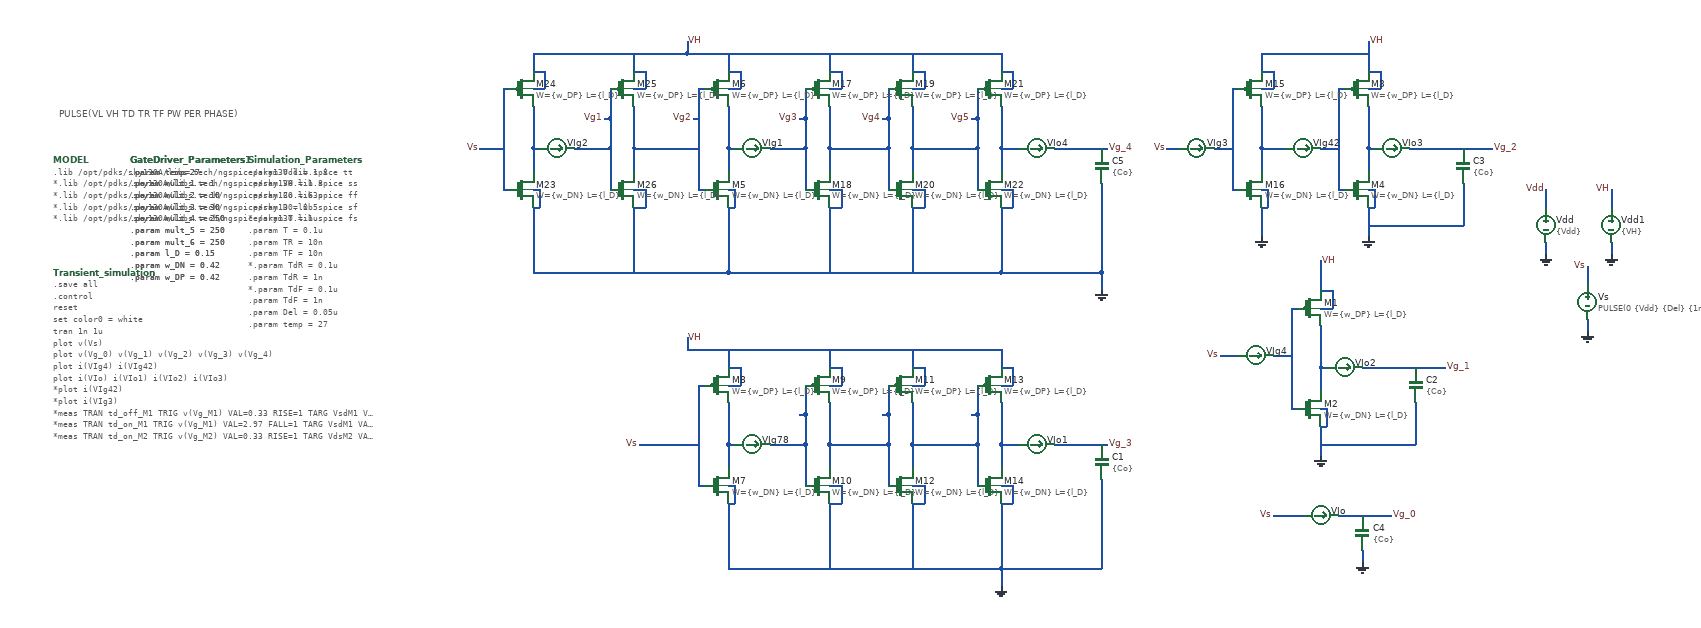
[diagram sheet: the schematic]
v {xschem version=3.4.5 file_version=1.2
}
G {}
K {}
V {}
S {}
E {}
T {PULSE(VL VH TD TR TF PW PER PHASE) 
} -1560 -1540 0 0 0.4 0.4 {}
N 950 -1400 950 -1370 {
lab=Vdd}
N 950 -1310 950 -1290 {
lab=GND}
N 1020 -1270 1020 -1240 {
lab=Vs}
N 1020 -1180 1020 -1160 {
lab=GND}
N 1060 -1400 1060 -1370 {
lab=VH}
N 1060 -1310 1060 -1290 {
lab=GND}
N 570 -1100 570 -1060 {
lab=#net1}
N 570 -1170 570 -1100 {
lab=#net1}
N 570 -1030 580 -1030 {
lab=GND}
N 580 -1030 580 -1000 {
lab=GND}
N 570 -1000 580 -1000 {
lab=GND}
N 570 -1200 590 -1200 {
lab=VH}
N 590 -1230 590 -1200 {
lab=VH}
N 570 -1230 590 -1230 {
lab=VH}
N 570 -1100 580 -1100 {
lab=#net1}
N 520 -1200 520 -1030 {
lab=#net2}
N 520 -1030 530 -1030 {
lab=#net2}
N 570 -1000 570 -950 {
lab=GND}
N 570 -1280 570 -1230 {
lab=VH}
N 640 -1100 730 -1100 {
lab=Vg_1}
N 570 -970 730 -970 {
lab=GND}
N 730 -1040 730 -970 {
lab=GND}
N 490 -1120 520 -1120 {
lab=#net2}
N 730 -1100 780 -1100 {
lab=Vg_1}
N 400 -1120 430 -1120 {
lab=Vs}
N 650 -1470 650 -1430 {
lab=#net3}
N 650 -1540 650 -1470 {
lab=#net3}
N 650 -1400 660 -1400 {
lab=GND}
N 660 -1400 660 -1370 {
lab=GND}
N 650 -1370 660 -1370 {
lab=GND}
N 650 -1570 670 -1570 {
lab=VH}
N 670 -1600 670 -1570 {
lab=VH}
N 650 -1600 670 -1600 {
lab=VH}
N 650 -1470 660 -1470 {
lab=#net3}
N 600 -1570 610 -1570 {
lab=#net4}
N 600 -1570 600 -1400 {
lab=#net4}
N 600 -1400 610 -1400 {
lab=#net4}
N 650 -1370 650 -1320 {
lab=GND}
N 650 -1650 650 -1600 {
lab=VH}
N 720 -1470 810 -1470 {
lab=Vg_2}
N 650 -1340 810 -1340 {
lab=GND}
N 810 -1410 810 -1340 {
lab=GND}
N 570 -1470 600 -1470 {
lab=#net4}
N 810 -1470 860 -1470 {
lab=Vg_2}
N 480 -1470 510 -1470 {
lab=#net5}
N 470 -1470 470 -1430 {
lab=#net5}
N 470 -1540 470 -1470 {
lab=#net5}
N 470 -1400 480 -1400 {
lab=GND}
N 480 -1400 480 -1370 {
lab=GND}
N 470 -1370 480 -1370 {
lab=GND}
N 470 -1570 490 -1570 {
lab=VH}
N 490 -1600 490 -1570 {
lab=VH}
N 470 -1600 490 -1600 {
lab=VH}
N 470 -1470 480 -1470 {
lab=#net5}
N 420 -1570 430 -1570 {
lab=#net6}
N 420 -1570 420 -1400 {
lab=#net6}
N 420 -1400 430 -1400 {
lab=#net6}
N 470 -1370 470 -1320 {
lab=GND}
N 390 -1470 420 -1470 {
lab=#net6}
N 470 -1610 470 -1600 {
lab=VH}
N 470 -1630 650 -1630 {
lab=VH}
N 310 -1470 330 -1470 {
lab=Vs}
N 470 -1630 470 -1610 {
lab=VH}
N 600 -850 640 -850 {
lab=Vg_0}
N 490 -850 540 -850 {
lab=Vs}
N 640 -790 640 -770 {
lab=GND}
N 640 -850 690 -850 {
lab=Vg_0}
N 120 -970 170 -970 {
lab=Vg_3}
N -500 -1150 -500 -1130 {
lab=VH}
N 170 -970 200 -970 {
lab=Vg_3}
N 200 -970 210 -970 {
lab=Vg_3}
N 50 -970 60 -970 {
lab=#net7}
N -430 -970 -430 -930 {
lab=#net8}
N -140 -760 30 -760 {
lab=GND}
N -310 -760 -140 -760 {
lab=GND}
N -550 -970 -480 -970 {
lab=Vs}
N -300 -970 -300 -900 {
lab=#net9}
N -430 -1040 -430 -970 {
lab=#net8}
N -300 -1020 -300 -970 {
lab=#net9}
N -260 -970 -260 -930 {
lab=#net10}
N -140 -1130 30 -1130 {
lab=VH}
N -310 -1130 -140 -1130 {
lab=VH}
N -500 -1130 -310 -1130 {
lab=VH}
N -580 -970 -550 -970 {
lab=Vs}
N 30 -760 30 -730 {
lab=GND}
N -260 -970 -220 -970 {
lab=#net10}
N -260 -1040 -260 -970 {
lab=#net10}
N -430 -900 -420 -900 {
lab=GND}
N -420 -900 -420 -870 {
lab=GND}
N -430 -870 -420 -870 {
lab=GND}
N -260 -900 -240 -900 {
lab=GND}
N -240 -900 -240 -870 {
lab=GND}
N -260 -870 -240 -870 {
lab=GND}
N -430 -1070 -410 -1070 {
lab=VH}
N -410 -1100 -410 -1070 {
lab=VH}
N -430 -1100 -410 -1100 {
lab=VH}
N -260 -1070 -240 -1070 {
lab=VH}
N -240 -1100 -240 -1070 {
lab=VH}
N -260 -1100 -240 -1100 {
lab=VH}
N -360 -970 -300 -970 {
lab=#net9}
N -430 -970 -420 -970 {
lab=#net8}
N -310 -1020 -300 -1020 {
lab=#net9}
N -300 -1070 -300 -1020 {
lab=#net9}
N -480 -1070 -470 -1070 {
lab=Vs}
N -480 -1070 -480 -900 {
lab=Vs}
N -480 -900 -470 -900 {
lab=Vs}
N -430 -870 -430 -760 {
lab=GND}
N -430 -760 -300 -760 {
lab=GND}
N -430 -1130 -430 -1100 {
lab=VH}
N -260 -1130 -260 -1100 {
lab=VH}
N -260 -870 -260 -760 {
lab=GND}
N -160 -970 -160 -900 {
lab=#net10}
N -160 -1020 -160 -970 {
lab=#net10}
N -120 -970 -120 -930 {
lab=#net11}
N -120 -970 -80 -970 {
lab=#net11}
N -120 -1040 -120 -970 {
lab=#net11}
N -120 -900 -100 -900 {
lab=GND}
N -100 -900 -100 -870 {
lab=GND}
N -120 -870 -100 -870 {
lab=GND}
N -120 -1070 -100 -1070 {
lab=VH}
N -100 -1100 -100 -1070 {
lab=VH}
N -120 -1100 -100 -1100 {
lab=VH}
N -220 -970 -160 -970 {
lab=#net10}
N -170 -1020 -160 -1020 {
lab=#net10}
N -160 -1070 -160 -1020 {
lab=#net10}
N -120 -1130 -120 -1100 {
lab=VH}
N -120 -870 -120 -760 {
lab=GND}
N -10 -970 -10 -900 {
lab=#net11}
N -10 -1020 -10 -970 {
lab=#net11}
N 30 -970 30 -930 {
lab=#net7}
N 30 -1040 30 -970 {
lab=#net7}
N 30 -900 50 -900 {
lab=GND}
N 50 -900 50 -870 {
lab=GND}
N 30 -870 50 -870 {
lab=GND}
N 30 -1070 50 -1070 {
lab=VH}
N 50 -1100 50 -1070 {
lab=VH}
N 30 -1100 50 -1100 {
lab=VH}
N -70 -970 -10 -970 {
lab=#net11}
N -20 -1020 -10 -1020 {
lab=#net11}
N -10 -1070 -10 -1020 {
lab=#net11}
N 30 -1130 30 -1100 {
lab=VH}
N 30 -870 30 -760 {
lab=GND}
N -80 -970 -60 -970 {
lab=#net11}
N 30 -970 60 -970 {
lab=#net7}
N 200 -910 200 -760 {
lab=GND}
N 30 -760 200 -760 {
lab=GND}
N 520 -1200 530 -1200 {
lab=#net2}
N 120 -1470 170 -1470 {
lab=Vg_4}
N -500 -1650 -500 -1630 {
lab=VH}
N 170 -1470 200 -1470 {
lab=Vg_4}
N 200 -1470 210 -1470 {
lab=Vg_4}
N 50 -1470 60 -1470 {
lab=#net12}
N -430 -1470 -430 -1430 {
lab=#net13}
N -140 -1260 30 -1260 {
lab=GND}
N -310 -1260 -140 -1260 {
lab=GND}
N -550 -1470 -480 -1470 {
lab=Vg2}
N -300 -1470 -300 -1400 {
lab=Vg3}
N -430 -1540 -430 -1470 {
lab=#net13}
N -300 -1520 -300 -1470 {
lab=Vg3}
N -260 -1470 -260 -1430 {
lab=Vg4}
N -140 -1630 30 -1630 {
lab=VH}
N -310 -1630 -140 -1630 {
lab=VH}
N -500 -1630 -310 -1630 {
lab=VH}
N 200 -1260 200 -1230 {
lab=GND}
N -260 -1470 -220 -1470 {
lab=Vg4}
N -260 -1540 -260 -1470 {
lab=Vg4}
N -430 -1400 -420 -1400 {
lab=GND}
N -420 -1400 -420 -1370 {
lab=GND}
N -430 -1370 -420 -1370 {
lab=GND}
N -260 -1400 -240 -1400 {
lab=GND}
N -240 -1400 -240 -1370 {
lab=GND}
N -260 -1370 -240 -1370 {
lab=GND}
N -430 -1570 -410 -1570 {
lab=VH}
N -410 -1600 -410 -1570 {
lab=VH}
N -430 -1600 -410 -1600 {
lab=VH}
N -260 -1570 -240 -1570 {
lab=VH}
N -240 -1600 -240 -1570 {
lab=VH}
N -260 -1600 -240 -1600 {
lab=VH}
N -360 -1470 -300 -1470 {
lab=Vg3}
N -430 -1470 -420 -1470 {
lab=#net13}
N -310 -1520 -300 -1520 {
lab=Vg3}
N -300 -1570 -300 -1520 {
lab=Vg3}
N -480 -1570 -470 -1570 {
lab=Vg2}
N -480 -1570 -480 -1400 {
lab=Vg2}
N -480 -1400 -470 -1400 {
lab=Vg2}
N -430 -1370 -430 -1260 {
lab=GND}
N -430 -1260 -300 -1260 {
lab=GND}
N -430 -1630 -430 -1600 {
lab=VH}
N -260 -1630 -260 -1600 {
lab=VH}
N -260 -1370 -260 -1260 {
lab=GND}
N -160 -1470 -160 -1400 {
lab=Vg4}
N -160 -1520 -160 -1470 {
lab=Vg4}
N -120 -1470 -120 -1430 {
lab=Vg5}
N -120 -1470 -80 -1470 {
lab=Vg5}
N -120 -1540 -120 -1470 {
lab=Vg5}
N -120 -1400 -100 -1400 {
lab=GND}
N -100 -1400 -100 -1370 {
lab=GND}
N -120 -1370 -100 -1370 {
lab=GND}
N -120 -1570 -100 -1570 {
lab=VH}
N -100 -1600 -100 -1570 {
lab=VH}
N -120 -1600 -100 -1600 {
lab=VH}
N -220 -1470 -160 -1470 {
lab=Vg4}
N -170 -1520 -160 -1520 {
lab=Vg4}
N -160 -1570 -160 -1520 {
lab=Vg4}
N -120 -1630 -120 -1600 {
lab=VH}
N -120 -1370 -120 -1260 {
lab=GND}
N -10 -1470 -10 -1400 {
lab=Vg5}
N -10 -1520 -10 -1470 {
lab=Vg5}
N 30 -1470 30 -1430 {
lab=#net12}
N 30 -1540 30 -1470 {
lab=#net12}
N 30 -1400 50 -1400 {
lab=GND}
N 50 -1400 50 -1370 {
lab=GND}
N 30 -1370 50 -1370 {
lab=GND}
N 30 -1570 50 -1570 {
lab=VH}
N 50 -1600 50 -1570 {
lab=VH}
N 30 -1600 50 -1600 {
lab=VH}
N -70 -1470 -10 -1470 {
lab=Vg5}
N -20 -1520 -10 -1520 {
lab=Vg5}
N -10 -1570 -10 -1520 {
lab=Vg5}
N 30 -1630 30 -1600 {
lab=VH}
N 30 -1370 30 -1260 {
lab=GND}
N -80 -1470 -60 -1470 {
lab=Vg5}
N 30 -1470 60 -1470 {
lab=#net12}
N 200 -1410 200 -1260 {
lab=GND}
N 30 -1260 200 -1260 {
lab=GND}
N -760 -1470 -760 -1430 {
lab=#net14}
N -630 -1470 -630 -1400 {
lab=Vg1}
N -760 -1540 -760 -1470 {
lab=#net14}
N -630 -1520 -630 -1470 {
lab=Vg1}
N -590 -1470 -590 -1430 {
lab=Vg2}
N -590 -1470 -550 -1470 {
lab=Vg2}
N -590 -1540 -590 -1470 {
lab=Vg2}
N -760 -1400 -750 -1400 {
lab=GND}
N -750 -1400 -750 -1370 {
lab=GND}
N -760 -1370 -750 -1370 {
lab=GND}
N -590 -1400 -570 -1400 {
lab=GND}
N -570 -1400 -570 -1370 {
lab=GND}
N -590 -1370 -570 -1370 {
lab=GND}
N -760 -1570 -740 -1570 {
lab=VH}
N -740 -1600 -740 -1570 {
lab=VH}
N -760 -1600 -740 -1600 {
lab=VH}
N -590 -1570 -570 -1570 {
lab=VH}
N -570 -1600 -570 -1570 {
lab=VH}
N -590 -1600 -570 -1600 {
lab=VH}
N -690 -1470 -630 -1470 {
lab=Vg1}
N -760 -1470 -750 -1470 {
lab=#net14}
N -640 -1520 -630 -1520 {
lab=Vg1}
N -630 -1570 -630 -1520 {
lab=Vg1}
N -810 -1570 -800 -1570 {
lab=Vs}
N -810 -1570 -810 -1400 {
lab=Vs}
N -810 -1400 -800 -1400 {
lab=Vs}
N -760 -1260 -430 -1260 {
lab=GND}
N -760 -1370 -760 -1260 {
lab=GND}
N -590 -1370 -590 -1260 {
lab=GND}
N -850 -1470 -810 -1470 {
lab=Vs}
N -760 -1630 -500 -1630 {
lab=VH}
N -760 -1630 -760 -1600 {
lab=VH}
N -590 -1630 -590 -1600 {
lab=VH}
N -490 -1520 -480 -1520 {
lab=Vg2}
C {vsource.sym} 950 -1340 0 0 {name=Vdd value=\{Vdd\} savecurrent=false}
C {lab_pin.sym} 950 -1400 0 0 {name=p5 sig_type=std_logic lab=Vdd}
C {gnd.sym} 950 -1290 0 0 {name=l2 lab=GND}
C {lab_pin.sym} 1020 -1270 0 0 {name=p4 sig_type=std_logic lab=Vs}
C {vsource.sym} 1020 -1210 0 1 {name=Vs value="PULSE(0 \{Vdd\} \{Del\} \{1n\} \{1n\} \{T*D\} \{T\} 0)" savecurrent=false}
C {gnd.sym} 1020 -1160 0 0 {name=l5 lab=GND}
C {code.sym} -1240 -1450 0 0 {name=Simulation_Parameters only_toplevel=false 

value="
.param Vdd = 1.8
.param VH = 1.8

.param Co = 63p

.param D = 0.5
*.param T = 1u
.param T = 0.1u
.param TR = 10n
.param TF = 10n
*.param TdR = 0.1u
.param TdR = 1n
*.param TdF = 0.1u
.param TdF = 1n
.param Del = 0.05u
.param temp = 27


"}
C {devices/code.sym} -1570 -1260 0 0 {name=Transient_simulation only_toplevel=false 

value="
.save all
.control
reset
set color0 = white
tran 1n 1u

plot v(Vs) 
plot v(Vg_0) v(Vg_1) v(Vg_2) v(Vg_3) v(Vg_4)
plot i(VIg4) i(VIg42)
plot i(VIo) i(VIo1) i(VIo2) i(VIo3)
*plot i(VIg42)
*plot i(VIg3)

*meas TRAN td_off_M1 TRIG v(Vg_M1) VAL=0.33 RISE=1 TARG VsdM1 VAL=0.33 RISE=1
*meas TRAN td_on_M1 TRIG v(Vg_M1) VAL=2.97 FALL=1 TARG VsdM1 VAL=2.97 FALL=1
*meas TRAN td_on_M2 TRIG v(Vg_M2) VAL=0.33 RISE=1 TARG VdsM2 VAL=2.97 FALL=1
*meas TRAN td_off_M2 TRIG v(Vg_M2) VAL=2.97 FALL=1 TARG VdsM2 VAL=0.33 RISE=1
*let TdR = td_off_M1 - td_on_M2 
*let TdF = td_on_M1 - td_off_M2
*print TdR TdF
.endc

.end
"}
C {code.sym} -1440 -1450 0 0 {name=GateDriver_Parameters only_toplevel=false 

value="
.param temp=27

.param mult_1 = 1
.param mult_2 = 10
.param mult_3 = 30
.param mult_4 = 250
.param mult_5 = 250
.param mult_6 = 250

.param l_D = 0.15
.param w_DN = 0.42
.param w_DP = 0.42



"}
C {vsource.sym} 1060 -1340 0 0 {name=Vdd1 value=\{VH\} savecurrent=false}
C {lab_pin.sym} 1060 -1400 0 0 {name=p1 sig_type=std_logic lab=VH
value=\{VH\}}
C {gnd.sym} 1060 -1290 0 0 {name=l1 lab=GND
value=\{VH\}}
C {code.sym} -1570 -1450 0 0 {name=MODEL only_toplevel=true spice_ignore=false
format="tcleval( @value )"
value="
.lib /opt/pdks/sky130A/libs.tech/ngspice/sky130.lib.spice tt
*.lib /opt/pdks/sky130A/libs.tech/ngspice/sky130.lib.spice ss
*.lib /opt/pdks/sky130A/libs.tech/ngspice/sky130.lib.spice ff
*.lib /opt/pdks/sky130A/libs.tech/ngspice/sky130.lib.spice sf
*.lib /opt/pdks/sky130A/libs.tech/ngspice/sky130.lib.spice fs
"}
C {ammeter.sym} 610 -1100 3 0 {name=VIo2 savecurrent=true spice_ignore=0}
C {lab_pin.sym} 570 -1280 0 1 {name=p8 sig_type=std_logic lab=VH
value=\{VH\}}
C {gnd.sym} 570 -950 0 0 {name=l4 lab=GND
value=\{VH\}}
C {capa.sym} 730 -1070 0 0 {name=C2
m=1
value=\{Co\}
footprint=1206
device="ceramic capacitor"}
C {lab_pin.sym} 400 -1120 0 0 {name=p9 sig_type=std_logic lab=Vs}
C {lab_pin.sym} 780 -1100 0 1 {name=p10 sig_type=std_logic lab=Vg_1}
C {ammeter.sym} 460 -1120 3 0 {name=VIg4 savecurrent=true spice_ignore=0}
C {ammeter.sym} 690 -1470 3 0 {name=VIo3 savecurrent=true spice_ignore=0}
C {lab_pin.sym} 650 -1650 0 1 {name=p11 sig_type=std_logic lab=VH
value=\{VH\}}
C {gnd.sym} 650 -1320 0 0 {name=l6 lab=GND
value=\{VH\}}
C {capa.sym} 810 -1440 0 0 {name=C3
m=1
value=\{Co\}
footprint=1206
device="ceramic capacitor"}
C {lab_pin.sym} 310 -1470 0 0 {name=p12 sig_type=std_logic lab=Vs}
C {lab_pin.sym} 860 -1470 0 1 {name=p13 sig_type=std_logic lab=Vg_2}
C {ammeter.sym} 540 -1470 3 0 {name=VIg42 savecurrent=true spice_ignore=0}
C {ammeter.sym} 360 -1470 3 0 {name=VIg3 savecurrent=true spice_ignore=0}
C {gnd.sym} 470 -1320 0 0 {name=l7 lab=GND
value=\{VH\}}
C {capa.sym} 640 -820 0 0 {name=C4
m=1
value=\{Co\}
footprint=1206
device="ceramic capacitor"}
C {ammeter.sym} 570 -850 3 0 {name=VIo savecurrent=true spice_ignore=0}
C {lab_pin.sym} 490 -850 0 0 {name=p14 sig_type=std_logic lab=Vs}
C {gnd.sym} 640 -770 0 0 {name=l8 lab=GND
value=\{VH\}}
C {lab_pin.sym} 690 -850 0 1 {name=p15 sig_type=std_logic lab=Vg_0}
C {capa.sym} 200 -940 0 0 {name=C1
m=1
value=\{Co\}
footprint=1206
device="ceramic capacitor"}
C {lab_pin.sym} -580 -970 0 0 {name=p2 sig_type=std_logic lab=Vs}
C {lab_pin.sym} -500 -1150 0 1 {name=p6 sig_type=std_logic lab=VH
value=\{VH\}}
C {lab_pin.sym} 210 -970 0 1 {name=p7 sig_type=std_logic lab=Vg_3}
C {ammeter.sym} 90 -970 3 0 {name=VIo1 savecurrent=true spice_ignore=0}
C {ammeter.sym} -390 -970 3 0 {name=VIg78 savecurrent=true spice_ignore=0}
C {sky130_fd_pr/nfet_01v8.sym} -450 -900 0 0 {name=M7
W=\{w_DN\}
L=\{l_D\}
nf=1
mult=\{mult_3\}
ad="'int((nf+1)/2) * W/nf * 0.29'" 
pd="'2*int((nf+1)/2) * (W/nf + 0.29)'"
as="'int((nf+2)/2) * W/nf * 0.29'" 
ps="'2*int((nf+2)/2) * (W/nf + 0.29)'"
nrd="'0.29 / W'" nrs="'0.29 / W'"
sa=0 sb=0 sd=0
model=nfet_01v8
spiceprefix=X
}
C {sky130_fd_pr/pfet_01v8.sym} -450 -1070 0 0 {name=M8
W=\{w_DP\}
L=\{l_D\}
nf=1
mult=\{mult_3*3\}
ad="'int((nf+1)/2) * W/nf * 0.29'" 
pd="'2*int((nf+1)/2) * (W/nf + 0.29)'"
as="'int((nf+2)/2) * W/nf * 0.29'" 
ps="'2*int((nf+2)/2) * (W/nf + 0.29)'"
nrd="'0.29 / W'" nrs="'0.29 / W'"
sa=0 sb=0 sd=0
model=pfet_01v8
spiceprefix=X
}
C {sky130_fd_pr/pfet_01v8.sym} -280 -1070 0 0 {name=M9
W=\{w_DP\}
L=\{l_D\}
nf=1
mult=\{mult_4*3\}
ad="'int((nf+1)/2) * W/nf * 0.29'" 
pd="'2*int((nf+1)/2) * (W/nf + 0.29)'"
as="'int((nf+2)/2) * W/nf * 0.29'" 
ps="'2*int((nf+2)/2) * (W/nf + 0.29)'"
nrd="'0.29 / W'" nrs="'0.29 / W'"
sa=0 sb=0 sd=0
model=pfet_01v8
spiceprefix=X
}
C {sky130_fd_pr/nfet_01v8.sym} -280 -900 0 0 {name=M10
W=\{w_DN\}
L=\{l_D\}
nf=1
mult=\{mult_4\}
ad="'int((nf+1)/2) * W/nf * 0.29'" 
pd="'2*int((nf+1)/2) * (W/nf + 0.29)'"
as="'int((nf+2)/2) * W/nf * 0.29'" 
ps="'2*int((nf+2)/2) * (W/nf + 0.29)'"
nrd="'0.29 / W'" nrs="'0.29 / W'"
sa=0 sb=0 sd=0
model=nfet_01v8
spiceprefix=X
}
C {sky130_fd_pr/pfet_01v8.sym} -140 -1070 0 0 {name=M11
W=\{w_DP\}
L=\{l_D\}
nf=1
mult=\{mult_5*3\}
ad="'int((nf+1)/2) * W/nf * 0.29'" 
pd="'2*int((nf+1)/2) * (W/nf + 0.29)'"
as="'int((nf+2)/2) * W/nf * 0.29'" 
ps="'2*int((nf+2)/2) * (W/nf + 0.29)'"
nrd="'0.29 / W'" nrs="'0.29 / W'"
sa=0 sb=0 sd=0
model=pfet_01v8
spiceprefix=X
}
C {sky130_fd_pr/nfet_01v8.sym} -140 -900 0 0 {name=M12
W=\{w_DN\}
L=\{l_D\}
nf=1
mult=\{mult_5\}
ad="'int((nf+1)/2) * W/nf * 0.29'" 
pd="'2*int((nf+1)/2) * (W/nf + 0.29)'"
as="'int((nf+2)/2) * W/nf * 0.29'" 
ps="'2*int((nf+2)/2) * (W/nf + 0.29)'"
nrd="'0.29 / W'" nrs="'0.29 / W'"
sa=0 sb=0 sd=0
model=nfet_01v8
spiceprefix=X
}
C {sky130_fd_pr/pfet_01v8.sym} 10 -1070 0 0 {name=M13
W=\{w_DP\}
L=\{l_D\}
nf=1
mult=\{mult_6*3\}
ad="'int((nf+1)/2) * W/nf * 0.29'" 
pd="'2*int((nf+1)/2) * (W/nf + 0.29)'"
as="'int((nf+2)/2) * W/nf * 0.29'" 
ps="'2*int((nf+2)/2) * (W/nf + 0.29)'"
nrd="'0.29 / W'" nrs="'0.29 / W'"
sa=0 sb=0 sd=0
model=pfet_01v8
spiceprefix=X
}
C {sky130_fd_pr/nfet_01v8.sym} 10 -900 0 0 {name=M14
W=\{w_DN\}
L=\{l_D\}
nf=1
mult=\{mult_6\}
ad="'int((nf+1)/2) * W/nf * 0.29'" 
pd="'2*int((nf+1)/2) * (W/nf + 0.29)'"
as="'int((nf+2)/2) * W/nf * 0.29'" 
ps="'2*int((nf+2)/2) * (W/nf + 0.29)'"
nrd="'0.29 / W'" nrs="'0.29 / W'"
sa=0 sb=0 sd=0
model=nfet_01v8
spiceprefix=X
}
C {gnd.sym} 30 -730 0 0 {name=l3 lab=GND
value=\{VH\}}
C {sky130_fd_pr/pfet_01v8.sym} 630 -1570 0 0 {name=M3
W=\{w_DP\}
L=\{l_D\}
nf=1
mult=\{mult_6*3\}
ad="'int((nf+1)/2) * W/nf * 0.29'" 
pd="'2*int((nf+1)/2) * (W/nf + 0.29)'"
as="'int((nf+2)/2) * W/nf * 0.29'" 
ps="'2*int((nf+2)/2) * (W/nf + 0.29)'"
nrd="'0.29 / W'" nrs="'0.29 / W'"
sa=0 sb=0 sd=0
model=pfet_01v8
spiceprefix=X
}
C {sky130_fd_pr/nfet_01v8.sym} 630 -1400 0 0 {name=M4
W=\{w_DN\}
L=\{l_D\}
nf=1
mult=\{mult_6\}
ad="'int((nf+1)/2) * W/nf * 0.29'" 
pd="'2*int((nf+1)/2) * (W/nf + 0.29)'"
as="'int((nf+2)/2) * W/nf * 0.29'" 
ps="'2*int((nf+2)/2) * (W/nf + 0.29)'"
nrd="'0.29 / W'" nrs="'0.29 / W'"
sa=0 sb=0 sd=0
model=nfet_01v8
spiceprefix=X
}
C {sky130_fd_pr/pfet_01v8.sym} 550 -1200 0 0 {name=M1
W=\{w_DP\}
L=\{l_D\}
nf=1
mult=\{mult_6*3\}
ad="'int((nf+1)/2) * W/nf * 0.29'" 
pd="'2*int((nf+1)/2) * (W/nf + 0.29)'"
as="'int((nf+2)/2) * W/nf * 0.29'" 
ps="'2*int((nf+2)/2) * (W/nf + 0.29)'"
nrd="'0.29 / W'" nrs="'0.29 / W'"
sa=0 sb=0 sd=0
model=pfet_01v8
spiceprefix=X
}
C {sky130_fd_pr/nfet_01v8.sym} 550 -1030 0 0 {name=M2
W=\{w_DN\}
L=\{l_D\}
nf=1
mult=\{mult_6\}
ad="'int((nf+1)/2) * W/nf * 0.29'" 
pd="'2*int((nf+1)/2) * (W/nf + 0.29)'"
as="'int((nf+2)/2) * W/nf * 0.29'" 
ps="'2*int((nf+2)/2) * (W/nf + 0.29)'"
nrd="'0.29 / W'" nrs="'0.29 / W'"
sa=0 sb=0 sd=0
model=nfet_01v8
spiceprefix=X
}
C {sky130_fd_pr/pfet_01v8.sym} 450 -1570 0 0 {name=M15
W=\{w_DP\}
L=\{l_D\}
nf=1
mult=\{mult_5*3\}
ad="'int((nf+1)/2) * W/nf * 0.29'" 
pd="'2*int((nf+1)/2) * (W/nf + 0.29)'"
as="'int((nf+2)/2) * W/nf * 0.29'" 
ps="'2*int((nf+2)/2) * (W/nf + 0.29)'"
nrd="'0.29 / W'" nrs="'0.29 / W'"
sa=0 sb=0 sd=0
model=pfet_01v8
spiceprefix=X
}
C {sky130_fd_pr/nfet_01v8.sym} 450 -1400 0 0 {name=M16
W=\{w_DN\}
L=\{l_D\}
nf=1
mult=\{mult_5\}
ad="'int((nf+1)/2) * W/nf * 0.29'" 
pd="'2*int((nf+1)/2) * (W/nf + 0.29)'"
as="'int((nf+2)/2) * W/nf * 0.29'" 
ps="'2*int((nf+2)/2) * (W/nf + 0.29)'"
nrd="'0.29 / W'" nrs="'0.29 / W'"
sa=0 sb=0 sd=0
model=nfet_01v8
spiceprefix=X
}
C {capa.sym} 200 -1440 0 0 {name=C5
m=1
value=\{Co\}
footprint=1206
device="ceramic capacitor"}
C {lab_pin.sym} -500 -1650 0 1 {name=p19 sig_type=std_logic lab=VH
value=\{VH\}}
C {lab_pin.sym} 210 -1470 0 1 {name=p20 sig_type=std_logic lab=Vg_4}
C {ammeter.sym} 90 -1470 3 0 {name=VIo4 savecurrent=true spice_ignore=0}
C {lab_pin.sym} -310 -1520 0 0 {name=p21 sig_type=std_logic lab=Vg3}
C {ammeter.sym} -390 -1470 3 0 {name=VIg1 savecurrent=true spice_ignore=0}
C {sky130_fd_pr/nfet_01v8.sym} -450 -1400 0 0 {name=M5
W=\{w_DN\}
L=\{l_D\}
nf=1
mult=\{mult_3\}
ad="'int((nf+1)/2) * W/nf * 0.29'" 
pd="'2*int((nf+1)/2) * (W/nf + 0.29)'"
as="'int((nf+2)/2) * W/nf * 0.29'" 
ps="'2*int((nf+2)/2) * (W/nf + 0.29)'"
nrd="'0.29 / W'" nrs="'0.29 / W'"
sa=0 sb=0 sd=0
model=nfet_01v8
spiceprefix=X
}
C {sky130_fd_pr/pfet_01v8.sym} -450 -1570 0 0 {name=M6
W=\{w_DP\}
L=\{l_D\}
nf=1
mult=\{mult_3*3\}
ad="'int((nf+1)/2) * W/nf * 0.29'" 
pd="'2*int((nf+1)/2) * (W/nf + 0.29)'"
as="'int((nf+2)/2) * W/nf * 0.29'" 
ps="'2*int((nf+2)/2) * (W/nf + 0.29)'"
nrd="'0.29 / W'" nrs="'0.29 / W'"
sa=0 sb=0 sd=0
model=pfet_01v8
spiceprefix=X
}
C {sky130_fd_pr/pfet_01v8.sym} -280 -1570 0 0 {name=M17
W=\{w_DP\}
L=\{l_D\}
nf=1
mult=\{mult_4*3\}
ad="'int((nf+1)/2) * W/nf * 0.29'" 
pd="'2*int((nf+1)/2) * (W/nf + 0.29)'"
as="'int((nf+2)/2) * W/nf * 0.29'" 
ps="'2*int((nf+2)/2) * (W/nf + 0.29)'"
nrd="'0.29 / W'" nrs="'0.29 / W'"
sa=0 sb=0 sd=0
model=pfet_01v8
spiceprefix=X
}
C {sky130_fd_pr/nfet_01v8.sym} -280 -1400 0 0 {name=M18
W=\{w_DN\}
L=\{l_D\}
nf=1
mult=\{mult_4\}
ad="'int((nf+1)/2) * W/nf * 0.29'" 
pd="'2*int((nf+1)/2) * (W/nf + 0.29)'"
as="'int((nf+2)/2) * W/nf * 0.29'" 
ps="'2*int((nf+2)/2) * (W/nf + 0.29)'"
nrd="'0.29 / W'" nrs="'0.29 / W'"
sa=0 sb=0 sd=0
model=nfet_01v8
spiceprefix=X
}
C {lab_pin.sym} -170 -1520 0 0 {name=p22 sig_type=std_logic lab=Vg4}
C {sky130_fd_pr/pfet_01v8.sym} -140 -1570 0 0 {name=M19
W=\{w_DP\}
L=\{l_D\}
nf=1
mult=\{mult_5*3\}
ad="'int((nf+1)/2) * W/nf * 0.29'" 
pd="'2*int((nf+1)/2) * (W/nf + 0.29)'"
as="'int((nf+2)/2) * W/nf * 0.29'" 
ps="'2*int((nf+2)/2) * (W/nf + 0.29)'"
nrd="'0.29 / W'" nrs="'0.29 / W'"
sa=0 sb=0 sd=0
model=pfet_01v8
spiceprefix=X
}
C {sky130_fd_pr/nfet_01v8.sym} -140 -1400 0 0 {name=M20
W=\{w_DN\}
L=\{l_D\}
nf=1
mult=\{mult_5\}
ad="'int((nf+1)/2) * W/nf * 0.29'" 
pd="'2*int((nf+1)/2) * (W/nf + 0.29)'"
as="'int((nf+2)/2) * W/nf * 0.29'" 
ps="'2*int((nf+2)/2) * (W/nf + 0.29)'"
nrd="'0.29 / W'" nrs="'0.29 / W'"
sa=0 sb=0 sd=0
model=nfet_01v8
spiceprefix=X
}
C {lab_pin.sym} -20 -1520 0 0 {name=p23 sig_type=std_logic lab=Vg5}
C {sky130_fd_pr/pfet_01v8.sym} 10 -1570 0 0 {name=M21
W=\{w_DP\}
L=\{l_D\}
nf=1
mult=\{mult_6*3\}
ad="'int((nf+1)/2) * W/nf * 0.29'" 
pd="'2*int((nf+1)/2) * (W/nf + 0.29)'"
as="'int((nf+2)/2) * W/nf * 0.29'" 
ps="'2*int((nf+2)/2) * (W/nf + 0.29)'"
nrd="'0.29 / W'" nrs="'0.29 / W'"
sa=0 sb=0 sd=0
model=pfet_01v8
spiceprefix=X
}
C {sky130_fd_pr/nfet_01v8.sym} 10 -1400 0 0 {name=M22
W=\{w_DN\}
L=\{l_D\}
nf=1
mult=\{mult_6\}
ad="'int((nf+1)/2) * W/nf * 0.29'" 
pd="'2*int((nf+1)/2) * (W/nf + 0.29)'"
as="'int((nf+2)/2) * W/nf * 0.29'" 
ps="'2*int((nf+2)/2) * (W/nf + 0.29)'"
nrd="'0.29 / W'" nrs="'0.29 / W'"
sa=0 sb=0 sd=0
model=nfet_01v8
spiceprefix=X
}
C {gnd.sym} 200 -1230 0 0 {name=l9 lab=GND
value=\{VH\}}
C {lab_pin.sym} -640 -1520 0 0 {name=p18 sig_type=std_logic lab=Vg1}
C {ammeter.sym} -720 -1470 3 0 {name=VIg2 savecurrent=true spice_ignore=0}
C {sky130_fd_pr/nfet_01v8.sym} -780 -1400 0 0 {name=M23
W=\{w_DN\}
L=\{l_D\}
nf=1
mult=\{mult_1\}
ad="'int((nf+1)/2) * W/nf * 0.29'" 
pd="'2*int((nf+1)/2) * (W/nf + 0.29)'"
as="'int((nf+2)/2) * W/nf * 0.29'" 
ps="'2*int((nf+2)/2) * (W/nf + 0.29)'"
nrd="'0.29 / W'" nrs="'0.29 / W'"
sa=0 sb=0 sd=0
model=nfet_01v8
spiceprefix=X
}
C {sky130_fd_pr/pfet_01v8.sym} -780 -1570 0 0 {name=M24
W=\{w_DP\}
L=\{l_D\}
nf=1
mult=\{mult_1*3\}
ad="'int((nf+1)/2) * W/nf * 0.29'" 
pd="'2*int((nf+1)/2) * (W/nf + 0.29)'"
as="'int((nf+2)/2) * W/nf * 0.29'" 
ps="'2*int((nf+2)/2) * (W/nf + 0.29)'"
nrd="'0.29 / W'" nrs="'0.29 / W'"
sa=0 sb=0 sd=0
model=pfet_01v8
spiceprefix=X
}
C {sky130_fd_pr/pfet_01v8.sym} -610 -1570 0 0 {name=M25
W=\{w_DP\}
L=\{l_D\}
nf=1
mult=\{mult_2*3\}
ad="'int((nf+1)/2) * W/nf * 0.29'" 
pd="'2*int((nf+1)/2) * (W/nf + 0.29)'"
as="'int((nf+2)/2) * W/nf * 0.29'" 
ps="'2*int((nf+2)/2) * (W/nf + 0.29)'"
nrd="'0.29 / W'" nrs="'0.29 / W'"
sa=0 sb=0 sd=0
model=pfet_01v8
spiceprefix=X
}
C {sky130_fd_pr/nfet_01v8.sym} -610 -1400 0 0 {name=M26
W=\{w_DN\}
L=\{l_D\}
nf=1
mult=\{mult_2\}
ad="'int((nf+1)/2) * W/nf * 0.29'" 
pd="'2*int((nf+1)/2) * (W/nf + 0.29)'"
as="'int((nf+2)/2) * W/nf * 0.29'" 
ps="'2*int((nf+2)/2) * (W/nf + 0.29)'"
nrd="'0.29 / W'" nrs="'0.29 / W'"
sa=0 sb=0 sd=0
model=nfet_01v8
spiceprefix=X
}
C {lab_pin.sym} -850 -1470 0 0 {name=p24 sig_type=std_logic lab=Vs}
C {lab_pin.sym} -490 -1520 0 0 {name=p3 sig_type=std_logic lab=Vg2}
C {code.sym} -1440 -1450 0 0 {name=GateDriver_Parameters1 only_toplevel=false 

value="
.param temp=27

.param mult_1 = 1
.param mult_2 = 10
.param mult_3 = 30
.param mult_4 = 250
.param mult_5 = 250
.param mult_6 = 250

.param l_D = 0.15
.param w_DN = 0.42
.param w_DP = 0.42



"}
